###############################################################
#  Generated by:      Cadence Innovus 21.14-s109_1
#  OS:                Linux x86_64(Host ID eecs2420p06.engin.umich.edu)
#  Generated on:      Sun Mar 26 16:31:44 2023
#  Design:            PE_POOL
#  Command:           write_lef_abstract /afs/umich.edu/class/eecs627/w23/groups/group4/CNN_LSTM/CNN_POOL_ReLU/apr/PE_POOL/data/PE_POOL.lef -specifyTopLayer 4 -stripePin -PGpinLayers 4
###############################################################

VERSION 5.8 ;

BUSBITCHARS "[]" ;
DIVIDERCHAR "/" ;

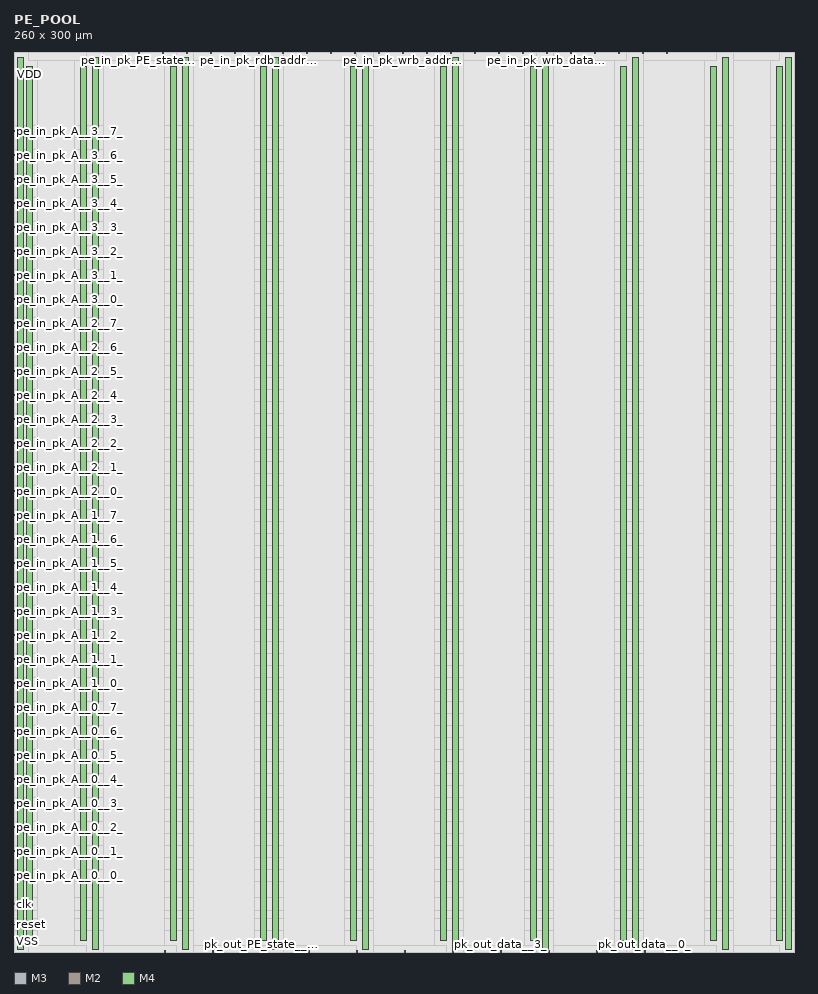
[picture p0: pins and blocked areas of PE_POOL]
MACRO PE_POOL
  CLASS BLOCK ;
  SIZE 260.000000 BY 300.000000 ;
  FOREIGN PE_POOL 0.000000 0.000000 ;
  ORIGIN 0 0 ;
  SYMMETRY X Y R90 ;
  PIN clk
    DIRECTION INPUT ;
    USE SIGNAL ;
    ANTENNAPARTIALMETALAREA 1.54 LAYER M3  ;
    ANTENNAPARTIALMETALSIDEAREA 0.0158 LAYER M3  ;
    ANTENNAMODEL OXIDE1 ;
    ANTENNAGATEAREA 0.8352 LAYER M3  ;
    ANTENNAMAXAREACAR 2.83812 LAYER M3  ;
    ANTENNAMAXSIDEAREACAR 0.0291906 LAYER M3  ;
    ANTENNAMAXCUTCAR 0.143678 LAYER V3  ;
    PORT
      LAYER M3 ;
        RECT 0.000000 15.900000 0.600000 16.100000 ;
    END
  END clk
  PIN reset
    DIRECTION INPUT ;
    USE SIGNAL ;
    ANTENNAPARTIALMETALAREA 1.3 LAYER M3  ;
    ANTENNAPARTIALMETALSIDEAREA 0.0134 LAYER M3  ;
    ANTENNAMODEL OXIDE1 ;
    ANTENNAGATEAREA 0.4848 LAYER M3  ;
    ANTENNAMAXAREACAR 18.5759 LAYER M3  ;
    ANTENNAMAXSIDEAREACAR 0.186427 LAYER M3  ;
    ANTENNAMAXCUTCAR 0.330033 LAYER V3  ;
    PORT
      LAYER M3 ;
        RECT 0.000000 9.100000 0.600000 9.300000 ;
    END
  END reset
  PIN pe_in_pk_PE_state__2_
    DIRECTION INPUT ;
    USE SIGNAL ;
    ANTENNAPARTIALMETALAREA 5.1 LAYER M2  ;
    ANTENNAPARTIALMETALSIDEAREA 0.051 LAYER M2  ;
    ANTENNAMODEL OXIDE1 ;
    ANTENNAGATEAREA 0.0624 LAYER M2  ;
    ANTENNAMAXAREACAR 84.1667 LAYER M2  ;
    ANTENNAMAXSIDEAREACAR 0.842308 LAYER M2  ;
    ANTENNAMAXCUTCAR 0.641026 LAYER V2  ;
    PORT
      LAYER M2 ;
        RECT 57.500000 299.400000 57.700000 300.000000 ;
    END
  END pe_in_pk_PE_state__2_
  PIN pe_in_pk_PE_state__1_
    DIRECTION INPUT ;
    USE SIGNAL ;
    ANTENNAPARTIALMETALAREA 3.98 LAYER M2  ;
    ANTENNAPARTIALMETALSIDEAREA 0.0398 LAYER M2  ;
    ANTENNAPARTIALCUTAREA 0.08 LAYER V2  ;
    ANTENNAPARTIALMETALAREA 0.84 LAYER M3  ;
    ANTENNAPARTIALMETALSIDEAREA 0.0088 LAYER M3  ;
    ANTENNAMODEL OXIDE1 ;
    ANTENNAGATEAREA 0.0624 LAYER M3  ;
    ANTENNAMAXAREACAR 30.641 LAYER M3  ;
    ANTENNAMAXSIDEAREACAR 0.319872 LAYER M3  ;
    ANTENNAMAXCUTCAR 1.92308 LAYER V3  ;
    PORT
      LAYER M2 ;
        RECT 49.500000 299.400000 49.700000 300.000000 ;
    END
  END pe_in_pk_PE_state__1_
  PIN pe_in_pk_PE_state__0_
    DIRECTION INPUT ;
    USE SIGNAL ;
    ANTENNAPARTIALMETALAREA 3.26 LAYER M2  ;
    ANTENNAPARTIALMETALSIDEAREA 0.0326 LAYER M2  ;
    ANTENNAPARTIALCUTAREA 0.08 LAYER V2  ;
    ANTENNAPARTIALMETALAREA 0.92 LAYER M3  ;
    ANTENNAPARTIALMETALSIDEAREA 0.0096 LAYER M3  ;
    ANTENNAMODEL OXIDE1 ;
    ANTENNAGATEAREA 0.0624 LAYER M3  ;
    ANTENNAMAXAREACAR 57.5641 LAYER M3  ;
    ANTENNAMAXSIDEAREACAR 0.589103 LAYER M3  ;
    ANTENNAMAXCUTCAR 1.92308 LAYER V3  ;
    PORT
      LAYER M2 ;
        RECT 41.500000 299.400000 41.700000 300.000000 ;
    END
  END pe_in_pk_PE_state__0_
  PIN pe_in_pk_A__3__7_
    DIRECTION INPUT ;
    USE SIGNAL ;
    ANTENNAPARTIALMETALAREA 3.58 LAYER M3  ;
    ANTENNAPARTIALMETALSIDEAREA 0.0358 LAYER M3  ;
    ANTENNAMODEL OXIDE1 ;
    ANTENNAGATEAREA 0.0624 LAYER M3  ;
    ANTENNAMAXAREACAR 68.141 LAYER M3  ;
    ANTENNAMAXSIDEAREACAR 0.688462 LAYER M3  ;
    ANTENNAMAXCUTCAR 1.92308 LAYER V3  ;
    PORT
      LAYER M3 ;
        RECT 0.000000 273.500000 0.600000 273.700000 ;
    END
  END pe_in_pk_A__3__7_
  PIN pe_in_pk_A__3__6_
    DIRECTION INPUT ;
    USE SIGNAL ;
    ANTENNAPARTIALMETALAREA 2.54 LAYER M3  ;
    ANTENNAPARTIALMETALSIDEAREA 0.0254 LAYER M3  ;
    ANTENNAMODEL OXIDE1 ;
    ANTENNAGATEAREA 0.0624 LAYER M3  ;
    ANTENNAMAXAREACAR 48.9103 LAYER M3  ;
    ANTENNAMAXSIDEAREACAR 0.496154 LAYER M3  ;
    ANTENNAMAXCUTCAR 1.92308 LAYER V3  ;
    PORT
      LAYER M3 ;
        RECT 0.000000 265.500000 0.600000 265.700000 ;
    END
  END pe_in_pk_A__3__6_
  PIN pe_in_pk_A__3__5_
    DIRECTION INPUT ;
    USE SIGNAL ;
    ANTENNAPARTIALMETALAREA 2.14 LAYER M3  ;
    ANTENNAPARTIALMETALSIDEAREA 0.0214 LAYER M3  ;
    ANTENNAMODEL OXIDE1 ;
    ANTENNAGATEAREA 0.0624 LAYER M3  ;
    ANTENNAMAXAREACAR 39.9359 LAYER M3  ;
    ANTENNAMAXSIDEAREACAR 0.40641 LAYER M3  ;
    ANTENNAMAXCUTCAR 1.92308 LAYER V3  ;
    PORT
      LAYER M3 ;
        RECT 0.000000 257.500000 0.600000 257.700000 ;
    END
  END pe_in_pk_A__3__5_
  PIN pe_in_pk_A__3__4_
    DIRECTION INPUT ;
    USE SIGNAL ;
    ANTENNAPARTIALMETALAREA 2.06 LAYER M3  ;
    ANTENNAPARTIALMETALSIDEAREA 0.0206 LAYER M3  ;
    ANTENNAMODEL OXIDE1 ;
    ANTENNAGATEAREA 0.0624 LAYER M3  ;
    ANTENNAMAXAREACAR 37.3718 LAYER M3  ;
    ANTENNAMAXSIDEAREACAR 0.380769 LAYER M3  ;
    ANTENNAMAXCUTCAR 1.92308 LAYER V3  ;
    PORT
      LAYER M3 ;
        RECT 0.000000 249.500000 0.600000 249.700000 ;
    END
  END pe_in_pk_A__3__4_
  PIN pe_in_pk_A__3__3_
    DIRECTION INPUT ;
    USE SIGNAL ;
    ANTENNAPARTIALMETALAREA 1.82 LAYER M3  ;
    ANTENNAPARTIALMETALSIDEAREA 0.0182 LAYER M3  ;
    ANTENNAMODEL OXIDE1 ;
    ANTENNAGATEAREA 0.0624 LAYER M3  ;
    ANTENNAMAXAREACAR 34.8077 LAYER M3  ;
    ANTENNAMAXSIDEAREACAR 0.355128 LAYER M3  ;
    ANTENNAMAXCUTCAR 1.92308 LAYER V3  ;
    PORT
      LAYER M3 ;
        RECT 0.000000 241.500000 0.600000 241.700000 ;
    END
  END pe_in_pk_A__3__3_
  PIN pe_in_pk_A__3__2_
    DIRECTION INPUT ;
    USE SIGNAL ;
    ANTENNAPARTIALMETALAREA 2.06 LAYER M3  ;
    ANTENNAPARTIALMETALSIDEAREA 0.0206 LAYER M3  ;
    ANTENNAMODEL OXIDE1 ;
    ANTENNAGATEAREA 0.0624 LAYER M3  ;
    ANTENNAMAXAREACAR 41.2179 LAYER M3  ;
    ANTENNAMAXSIDEAREACAR 0.419231 LAYER M3  ;
    ANTENNAMAXCUTCAR 1.92308 LAYER V3  ;
    PORT
      LAYER M3 ;
        RECT 0.000000 233.500000 0.600000 233.700000 ;
    END
  END pe_in_pk_A__3__2_
  PIN pe_in_pk_A__3__1_
    DIRECTION INPUT ;
    USE SIGNAL ;
    ANTENNAPARTIALMETALAREA 2.14 LAYER M3  ;
    ANTENNAPARTIALMETALSIDEAREA 0.0214 LAYER M3  ;
    ANTENNAMODEL OXIDE1 ;
    ANTENNAGATEAREA 0.0624 LAYER M3  ;
    ANTENNAMAXAREACAR 38.6538 LAYER M3  ;
    ANTENNAMAXSIDEAREACAR 0.39359 LAYER M3  ;
    ANTENNAMAXCUTCAR 1.92308 LAYER V3  ;
    PORT
      LAYER M3 ;
        RECT 0.000000 225.500000 0.600000 225.700000 ;
    END
  END pe_in_pk_A__3__1_
  PIN pe_in_pk_A__3__0_
    DIRECTION INPUT ;
    USE SIGNAL ;
    ANTENNAPARTIALMETALAREA 2.06 LAYER M3  ;
    ANTENNAPARTIALMETALSIDEAREA 0.0206 LAYER M3  ;
    ANTENNAMODEL OXIDE1 ;
    ANTENNAGATEAREA 0.0624 LAYER M3  ;
    ANTENNAMAXAREACAR 46.3462 LAYER M3  ;
    ANTENNAMAXSIDEAREACAR 0.470513 LAYER M3  ;
    ANTENNAMAXCUTCAR 1.92308 LAYER V3  ;
    PORT
      LAYER M3 ;
        RECT 0.000000 217.500000 0.600000 217.700000 ;
    END
  END pe_in_pk_A__3__0_
  PIN pe_in_pk_A__2__7_
    DIRECTION INPUT ;
    USE SIGNAL ;
    ANTENNAPARTIALMETALAREA 1.82 LAYER M3  ;
    ANTENNAPARTIALMETALSIDEAREA 0.0182 LAYER M3  ;
    ANTENNAMODEL OXIDE1 ;
    ANTENNAGATEAREA 0.0624 LAYER M3  ;
    ANTENNAMAXAREACAR 42.5 LAYER M3  ;
    ANTENNAMAXSIDEAREACAR 0.432051 LAYER M3  ;
    ANTENNAMAXCUTCAR 1.92308 LAYER V3  ;
    PORT
      LAYER M3 ;
        RECT 0.000000 209.500000 0.600000 209.700000 ;
    END
  END pe_in_pk_A__2__7_
  PIN pe_in_pk_A__2__6_
    DIRECTION INPUT ;
    USE SIGNAL ;
    ANTENNAPARTIALMETALAREA 1.58 LAYER M3  ;
    ANTENNAPARTIALMETALSIDEAREA 0.0158 LAYER M3  ;
    ANTENNAMODEL OXIDE1 ;
    ANTENNAGATEAREA 0.0624 LAYER M3  ;
    ANTENNAMAXAREACAR 38.6538 LAYER M3  ;
    ANTENNAMAXSIDEAREACAR 0.39359 LAYER M3  ;
    ANTENNAMAXCUTCAR 1.92308 LAYER V3  ;
    PORT
      LAYER M3 ;
        RECT 0.000000 201.500000 0.600000 201.700000 ;
    END
  END pe_in_pk_A__2__6_
  PIN pe_in_pk_A__2__5_
    DIRECTION INPUT ;
    USE SIGNAL ;
    ANTENNAPARTIALMETALAREA 1.74 LAYER M3  ;
    ANTENNAPARTIALMETALSIDEAREA 0.0174 LAYER M3  ;
    ANTENNAMODEL OXIDE1 ;
    ANTENNAGATEAREA 0.0624 LAYER M3  ;
    ANTENNAMAXAREACAR 38.6538 LAYER M3  ;
    ANTENNAMAXSIDEAREACAR 0.39359 LAYER M3  ;
    ANTENNAMAXCUTCAR 1.92308 LAYER V3  ;
    PORT
      LAYER M3 ;
        RECT 0.000000 193.500000 0.600000 193.700000 ;
    END
  END pe_in_pk_A__2__5_
  PIN pe_in_pk_A__2__4_
    DIRECTION INPUT ;
    USE SIGNAL ;
    ANTENNAPARTIALMETALAREA 1.9 LAYER M3  ;
    ANTENNAPARTIALMETALSIDEAREA 0.019 LAYER M3  ;
    ANTENNAMODEL OXIDE1 ;
    ANTENNAGATEAREA 0.0624 LAYER M3  ;
    ANTENNAMAXAREACAR 36.0897 LAYER M3  ;
    ANTENNAMAXSIDEAREACAR 0.367949 LAYER M3  ;
    ANTENNAMAXCUTCAR 1.92308 LAYER V3  ;
    PORT
      LAYER M3 ;
        RECT 0.000000 185.500000 0.600000 185.700000 ;
    END
  END pe_in_pk_A__2__4_
  PIN pe_in_pk_A__2__3_
    DIRECTION INPUT ;
    USE SIGNAL ;
    ANTENNAPARTIALMETALAREA 1.66 LAYER M3  ;
    ANTENNAPARTIALMETALSIDEAREA 0.0166 LAYER M3  ;
    ANTENNAMODEL OXIDE1 ;
    ANTENNAGATEAREA 0.0624 LAYER M3  ;
    ANTENNAMAXAREACAR 38.6538 LAYER M3  ;
    ANTENNAMAXSIDEAREACAR 0.39359 LAYER M3  ;
    ANTENNAMAXCUTCAR 1.92308 LAYER V3  ;
    PORT
      LAYER M3 ;
        RECT 0.000000 177.500000 0.600000 177.700000 ;
    END
  END pe_in_pk_A__2__3_
  PIN pe_in_pk_A__2__2_
    DIRECTION INPUT ;
    USE SIGNAL ;
    ANTENNAPARTIALMETALAREA 1.66 LAYER M3  ;
    ANTENNAPARTIALMETALSIDEAREA 0.0166 LAYER M3  ;
    ANTENNAMODEL OXIDE1 ;
    ANTENNAGATEAREA 0.0624 LAYER M3  ;
    ANTENNAMAXAREACAR 32.2436 LAYER M3  ;
    ANTENNAMAXSIDEAREACAR 0.329487 LAYER M3  ;
    ANTENNAMAXCUTCAR 1.92308 LAYER V3  ;
    PORT
      LAYER M3 ;
        RECT 0.000000 169.500000 0.600000 169.700000 ;
    END
  END pe_in_pk_A__2__2_
  PIN pe_in_pk_A__2__1_
    DIRECTION INPUT ;
    USE SIGNAL ;
    ANTENNAPARTIALMETALAREA 1.66 LAYER M3  ;
    ANTENNAPARTIALMETALSIDEAREA 0.0166 LAYER M3  ;
    ANTENNAMODEL OXIDE1 ;
    ANTENNAGATEAREA 0.0624 LAYER M3  ;
    ANTENNAMAXAREACAR 34.8077 LAYER M3  ;
    ANTENNAMAXSIDEAREACAR 0.355128 LAYER M3  ;
    ANTENNAMAXCUTCAR 1.92308 LAYER V3  ;
    PORT
      LAYER M3 ;
        RECT 0.000000 161.500000 0.600000 161.700000 ;
    END
  END pe_in_pk_A__2__1_
  PIN pe_in_pk_A__2__0_
    DIRECTION INPUT ;
    USE SIGNAL ;
    ANTENNAPARTIALMETALAREA 1.66 LAYER M3  ;
    ANTENNAPARTIALMETALSIDEAREA 0.0166 LAYER M3  ;
    ANTENNAMODEL OXIDE1 ;
    ANTENNAGATEAREA 0.0624 LAYER M3  ;
    ANTENNAMAXAREACAR 37.3718 LAYER M3  ;
    ANTENNAMAXSIDEAREACAR 0.380769 LAYER M3  ;
    ANTENNAMAXCUTCAR 1.92308 LAYER V3  ;
    PORT
      LAYER M3 ;
        RECT 0.000000 153.500000 0.600000 153.700000 ;
    END
  END pe_in_pk_A__2__0_
  PIN pe_in_pk_A__1__7_
    DIRECTION INPUT ;
    USE SIGNAL ;
    ANTENNAPARTIALMETALAREA 1.42 LAYER M3  ;
    ANTENNAPARTIALMETALSIDEAREA 0.0142 LAYER M3  ;
    ANTENNAMODEL OXIDE1 ;
    ANTENNAGATEAREA 0.0624 LAYER M3  ;
    ANTENNAMAXAREACAR 39.9359 LAYER M3  ;
    ANTENNAMAXSIDEAREACAR 0.40641 LAYER M3  ;
    ANTENNAMAXCUTCAR 1.92308 LAYER V3  ;
    PORT
      LAYER M3 ;
        RECT 0.000000 145.500000 0.600000 145.700000 ;
    END
  END pe_in_pk_A__1__7_
  PIN pe_in_pk_A__1__6_
    DIRECTION INPUT ;
    USE SIGNAL ;
    ANTENNAPARTIALMETALAREA 1.5 LAYER M3  ;
    ANTENNAPARTIALMETALSIDEAREA 0.015 LAYER M3  ;
    ANTENNAPARTIALCUTAREA 0.08 LAYER V3  ;
    ANTENNAPARTIALMETALAREA 0.28 LAYER M4  ;
    ANTENNAPARTIALMETALSIDEAREA 0.0032 LAYER M4  ;
    ANTENNAMODEL OXIDE1 ;
    ANTENNAGATEAREA 0.0624 LAYER M4  ;
    ANTENNAMAXAREACAR 36.4103 LAYER M4  ;
    ANTENNAMAXSIDEAREACAR 0.383974 LAYER M4  ;
    ANTENNAMAXCUTCAR 3.20513 LAYER V4  ;
    PORT
      LAYER M3 ;
        RECT 0.000000 137.500000 0.600000 137.700000 ;
    END
  END pe_in_pk_A__1__6_
  PIN pe_in_pk_A__1__5_
    DIRECTION INPUT ;
    USE SIGNAL ;
    ANTENNAPARTIALMETALAREA 1.74 LAYER M3  ;
    ANTENNAPARTIALMETALSIDEAREA 0.0174 LAYER M3  ;
    ANTENNAMODEL OXIDE1 ;
    ANTENNAGATEAREA 0.0624 LAYER M3  ;
    ANTENNAMAXAREACAR 47.6282 LAYER M3  ;
    ANTENNAMAXSIDEAREACAR 0.483333 LAYER M3  ;
    ANTENNAMAXCUTCAR 1.92308 LAYER V3  ;
    PORT
      LAYER M3 ;
        RECT 0.000000 129.500000 0.600000 129.700000 ;
    END
  END pe_in_pk_A__1__5_
  PIN pe_in_pk_A__1__4_
    DIRECTION INPUT ;
    USE SIGNAL ;
    ANTENNAPARTIALMETALAREA 1.74 LAYER M3  ;
    ANTENNAPARTIALMETALSIDEAREA 0.0174 LAYER M3  ;
    ANTENNAMODEL OXIDE1 ;
    ANTENNAGATEAREA 0.0624 LAYER M3  ;
    ANTENNAMAXAREACAR 45.0641 LAYER M3  ;
    ANTENNAMAXSIDEAREACAR 0.457692 LAYER M3  ;
    ANTENNAMAXCUTCAR 1.92308 LAYER V3  ;
    PORT
      LAYER M3 ;
        RECT 0.000000 121.500000 0.600000 121.700000 ;
    END
  END pe_in_pk_A__1__4_
  PIN pe_in_pk_A__1__3_
    DIRECTION INPUT ;
    USE SIGNAL ;
    ANTENNAPARTIALMETALAREA 1.74 LAYER M3  ;
    ANTENNAPARTIALMETALSIDEAREA 0.0174 LAYER M3  ;
    ANTENNAMODEL OXIDE1 ;
    ANTENNAGATEAREA 0.0624 LAYER M3  ;
    ANTENNAMAXAREACAR 33.5256 LAYER M3  ;
    ANTENNAMAXSIDEAREACAR 0.342308 LAYER M3  ;
    ANTENNAMAXCUTCAR 1.92308 LAYER V3  ;
    PORT
      LAYER M3 ;
        RECT 0.000000 113.500000 0.600000 113.700000 ;
    END
  END pe_in_pk_A__1__3_
  PIN pe_in_pk_A__1__2_
    DIRECTION INPUT ;
    USE SIGNAL ;
    ANTENNAPARTIALMETALAREA 1.82 LAYER M3  ;
    ANTENNAPARTIALMETALSIDEAREA 0.0182 LAYER M3  ;
    ANTENNAMODEL OXIDE1 ;
    ANTENNAGATEAREA 0.0624 LAYER M3  ;
    ANTENNAMAXAREACAR 56.6026 LAYER M3  ;
    ANTENNAMAXSIDEAREACAR 0.573077 LAYER M3  ;
    ANTENNAMAXCUTCAR 1.92308 LAYER V3  ;
    PORT
      LAYER M3 ;
        RECT 0.000000 105.500000 0.600000 105.700000 ;
    END
  END pe_in_pk_A__1__2_
  PIN pe_in_pk_A__1__1_
    DIRECTION INPUT ;
    USE SIGNAL ;
    ANTENNAPARTIALMETALAREA 1.74 LAYER M3  ;
    ANTENNAPARTIALMETALSIDEAREA 0.0174 LAYER M3  ;
    ANTENNAMODEL OXIDE1 ;
    ANTENNAGATEAREA 0.0624 LAYER M3  ;
    ANTENNAMAXAREACAR 52.7564 LAYER M3  ;
    ANTENNAMAXSIDEAREACAR 0.534615 LAYER M3  ;
    ANTENNAMAXCUTCAR 1.28205 LAYER V3  ;
    PORT
      LAYER M3 ;
        RECT 0.000000 97.500000 0.600000 97.700000 ;
    END
  END pe_in_pk_A__1__1_
  PIN pe_in_pk_A__1__0_
    DIRECTION INPUT ;
    USE SIGNAL ;
    ANTENNAPARTIALMETALAREA 1.5 LAYER M3  ;
    ANTENNAPARTIALMETALSIDEAREA 0.015 LAYER M3  ;
    ANTENNAMODEL OXIDE1 ;
    ANTENNAGATEAREA 0.0624 LAYER M3  ;
    ANTENNAMAXAREACAR 32.2436 LAYER M3  ;
    ANTENNAMAXSIDEAREACAR 0.329487 LAYER M3  ;
    ANTENNAMAXCUTCAR 1.92308 LAYER V3  ;
    PORT
      LAYER M3 ;
        RECT 0.000000 89.500000 0.600000 89.700000 ;
    END
  END pe_in_pk_A__1__0_
  PIN pe_in_pk_A__0__7_
    DIRECTION INPUT ;
    USE SIGNAL ;
    ANTENNAPARTIALMETALAREA 1.82 LAYER M3  ;
    ANTENNAPARTIALMETALSIDEAREA 0.0182 LAYER M3  ;
    ANTENNAMODEL OXIDE1 ;
    ANTENNAGATEAREA 0.0624 LAYER M3  ;
    ANTENNAMAXAREACAR 50.1923 LAYER M3  ;
    ANTENNAMAXSIDEAREACAR 0.508974 LAYER M3  ;
    ANTENNAMAXCUTCAR 1.28205 LAYER V3  ;
    PORT
      LAYER M3 ;
        RECT 0.000000 81.500000 0.600000 81.700000 ;
    END
  END pe_in_pk_A__0__7_
  PIN pe_in_pk_A__0__6_
    DIRECTION INPUT ;
    USE SIGNAL ;
    ANTENNAPARTIALMETALAREA 1.78 LAYER M3  ;
    ANTENNAPARTIALMETALSIDEAREA 0.0182 LAYER M3  ;
    ANTENNAMODEL OXIDE1 ;
    ANTENNAGATEAREA 0.0624 LAYER M3  ;
    ANTENNAMAXAREACAR 32.8846 LAYER M3  ;
    ANTENNAMAXSIDEAREACAR 0.342308 LAYER M3  ;
    ANTENNAMAXCUTCAR 1.92308 LAYER V3  ;
    PORT
      LAYER M3 ;
        RECT 0.000000 73.500000 0.600000 73.700000 ;
    END
  END pe_in_pk_A__0__6_
  PIN pe_in_pk_A__0__5_
    DIRECTION INPUT ;
    USE SIGNAL ;
    ANTENNAPARTIALMETALAREA 1.66 LAYER M3  ;
    ANTENNAPARTIALMETALSIDEAREA 0.0166 LAYER M3  ;
    ANTENNAPARTIALCUTAREA 0.08 LAYER V3  ;
    ANTENNAPARTIALMETALAREA 0.68 LAYER M4  ;
    ANTENNAPARTIALMETALSIDEAREA 0.0072 LAYER M4  ;
    ANTENNAMODEL OXIDE1 ;
    ANTENNAGATEAREA 0.0624 LAYER M4  ;
    ANTENNAMAXAREACAR 17.1795 LAYER M4  ;
    ANTENNAMAXSIDEAREACAR 0.191667 LAYER M4  ;
    ANTENNAMAXCUTCAR 3.20513 LAYER V4  ;
    PORT
      LAYER M3 ;
        RECT 0.000000 65.500000 0.600000 65.700000 ;
    END
  END pe_in_pk_A__0__5_
  PIN pe_in_pk_A__0__4_
    DIRECTION INPUT ;
    USE SIGNAL ;
    ANTENNAPARTIALMETALAREA 1.5 LAYER M3  ;
    ANTENNAPARTIALMETALSIDEAREA 0.015 LAYER M3  ;
    ANTENNAMODEL OXIDE1 ;
    ANTENNAGATEAREA 0.0624 LAYER M3  ;
    ANTENNAMAXAREACAR 36.0897 LAYER M3  ;
    ANTENNAMAXSIDEAREACAR 0.367949 LAYER M3  ;
    ANTENNAMAXCUTCAR 1.92308 LAYER V3  ;
    PORT
      LAYER M3 ;
        RECT 0.000000 57.500000 0.600000 57.700000 ;
    END
  END pe_in_pk_A__0__4_
  PIN pe_in_pk_A__0__3_
    DIRECTION INPUT ;
    USE SIGNAL ;
    ANTENNAPARTIALMETALAREA 2.14 LAYER M3  ;
    ANTENNAPARTIALMETALSIDEAREA 0.0214 LAYER M3  ;
    ANTENNAMODEL OXIDE1 ;
    ANTENNAGATEAREA 0.0624 LAYER M3  ;
    ANTENNAMAXAREACAR 42.5 LAYER M3  ;
    ANTENNAMAXSIDEAREACAR 0.432051 LAYER M3  ;
    ANTENNAMAXCUTCAR 1.92308 LAYER V3  ;
    PORT
      LAYER M3 ;
        RECT 0.000000 49.500000 0.600000 49.700000 ;
    END
  END pe_in_pk_A__0__3_
  PIN pe_in_pk_A__0__2_
    DIRECTION INPUT ;
    USE SIGNAL ;
    ANTENNAPARTIALMETALAREA 1.66 LAYER M3  ;
    ANTENNAPARTIALMETALSIDEAREA 0.0166 LAYER M3  ;
    ANTENNAMODEL OXIDE1 ;
    ANTENNAGATEAREA 0.0624 LAYER M3  ;
    ANTENNAMAXAREACAR 32.2436 LAYER M3  ;
    ANTENNAMAXSIDEAREACAR 0.329487 LAYER M3  ;
    ANTENNAMAXCUTCAR 1.92308 LAYER V3  ;
    PORT
      LAYER M3 ;
        RECT 0.000000 41.500000 0.600000 41.700000 ;
    END
  END pe_in_pk_A__0__2_
  PIN pe_in_pk_A__0__1_
    DIRECTION INPUT ;
    USE SIGNAL ;
    ANTENNAPARTIALMETALAREA 1.58 LAYER M3  ;
    ANTENNAPARTIALMETALSIDEAREA 0.0158 LAYER M3  ;
    ANTENNAMODEL OXIDE1 ;
    ANTENNAGATEAREA 0.0624 LAYER M3  ;
    ANTENNAMAXAREACAR 29.6795 LAYER M3  ;
    ANTENNAMAXSIDEAREACAR 0.303846 LAYER M3  ;
    ANTENNAMAXCUTCAR 1.92308 LAYER V3  ;
    PORT
      LAYER M3 ;
        RECT 0.000000 33.500000 0.600000 33.700000 ;
    END
  END pe_in_pk_A__0__1_
  PIN pe_in_pk_A__0__0_
    DIRECTION INPUT ;
    USE SIGNAL ;
    ANTENNAPARTIALMETALAREA 1.66 LAYER M3  ;
    ANTENNAPARTIALMETALSIDEAREA 0.0166 LAYER M3  ;
    ANTENNAMODEL OXIDE1 ;
    ANTENNAGATEAREA 0.0624 LAYER M3  ;
    ANTENNAMAXAREACAR 46.3462 LAYER M3  ;
    ANTENNAMAXSIDEAREACAR 0.470513 LAYER M3  ;
    ANTENNAMAXCUTCAR 1.92308 LAYER V3  ;
    PORT
      LAYER M3 ;
        RECT 0.000000 25.500000 0.600000 25.700000 ;
    END
  END pe_in_pk_A__0__0_
  PIN pe_in_pk_wrb_data__7_
    DIRECTION INPUT ;
    USE SIGNAL ;
    ANTENNAPARTIALMETALAREA 5.74 LAYER M2  ;
    ANTENNAPARTIALMETALSIDEAREA 0.0574 LAYER M2  ;
    ANTENNAPARTIALCUTAREA 0.08 LAYER V2  ;
    ANTENNAPARTIALMETALAREA 5 LAYER M3  ;
    ANTENNAPARTIALMETALSIDEAREA 0.0504 LAYER M3  ;
    ANTENNAMODEL OXIDE1 ;
    ANTENNAGATEAREA 0.1272 LAYER M3  ;
    ANTENNAMAXAREACAR 43.1447 LAYER M3  ;
    ANTENNAMAXSIDEAREACAR 0.437736 LAYER M3  ;
    ANTENNAMAXCUTCAR 1.25786 LAYER V3  ;
    PORT
      LAYER M2 ;
        RECT 217.500000 299.400000 217.700000 300.000000 ;
    END
  END pe_in_pk_wrb_data__7_
  PIN pe_in_pk_wrb_data__6_
    DIRECTION INPUT ;
    USE SIGNAL ;
    ANTENNAPARTIALMETALAREA 3.34 LAYER M2  ;
    ANTENNAPARTIALMETALSIDEAREA 0.0334 LAYER M2  ;
    ANTENNAPARTIALCUTAREA 0.08 LAYER V2  ;
    ANTENNAPARTIALMETALAREA 3.64 LAYER M3  ;
    ANTENNAPARTIALMETALSIDEAREA 0.0368 LAYER M3  ;
    ANTENNAMODEL OXIDE1 ;
    ANTENNAGATEAREA 0.0624 LAYER M3  ;
    ANTENNAMAXAREACAR 62.6923 LAYER M3  ;
    ANTENNAMAXSIDEAREACAR 0.640385 LAYER M3  ;
    ANTENNAMAXCUTCAR 1.92308 LAYER V3  ;
    PORT
      LAYER M2 ;
        RECT 209.500000 299.400000 209.700000 300.000000 ;
    END
  END pe_in_pk_wrb_data__6_
  PIN pe_in_pk_wrb_data__5_
    DIRECTION INPUT ;
    USE SIGNAL ;
    ANTENNAPARTIALMETALAREA 7.42 LAYER M2  ;
    ANTENNAPARTIALMETALSIDEAREA 0.0742 LAYER M2  ;
    ANTENNAPARTIALCUTAREA 0.08 LAYER V2  ;
    ANTENNAPARTIALMETALAREA 1.8 LAYER M3  ;
    ANTENNAPARTIALMETALSIDEAREA 0.0184 LAYER M3  ;
    ANTENNAMODEL OXIDE1 ;
    ANTENNAGATEAREA 0.1272 LAYER M3  ;
    ANTENNAMAXAREACAR 18.6164 LAYER M3  ;
    ANTENNAMAXSIDEAREACAR 0.192453 LAYER M3  ;
    ANTENNAMAXCUTCAR 1.25786 LAYER V3  ;
    PORT
      LAYER M2 ;
        RECT 201.500000 299.400000 201.700000 300.000000 ;
    END
  END pe_in_pk_wrb_data__5_
  PIN pe_in_pk_wrb_data__4_
    DIRECTION INPUT ;
    USE SIGNAL ;
    ANTENNAPARTIALMETALAREA 6.48 LAYER M2  ;
    ANTENNAPARTIALMETALSIDEAREA 0.0648 LAYER M2  ;
    ANTENNAMODEL OXIDE1 ;
    ANTENNAGATEAREA 0.0624 LAYER M2  ;
    ANTENNAMAXAREACAR 106.282 LAYER M2  ;
    ANTENNAMAXSIDEAREACAR 1.06346 LAYER M2  ;
    ANTENNAMAXCUTCAR 0.641026 LAYER V2  ;
    PORT
      LAYER M2 ;
        RECT 193.500000 299.400000 193.700000 300.000000 ;
    END
  END pe_in_pk_wrb_data__4_
  PIN pe_in_pk_wrb_data__3_
    DIRECTION INPUT ;
    USE SIGNAL ;
    ANTENNAPARTIALMETALAREA 3.42 LAYER M2  ;
    ANTENNAPARTIALMETALSIDEAREA 0.0342 LAYER M2  ;
    ANTENNAMODEL OXIDE1 ;
    ANTENNAGATEAREA 0.0624 LAYER M2  ;
    ANTENNAMAXAREACAR 57.2436 LAYER M2  ;
    ANTENNAMAXSIDEAREACAR 0.573077 LAYER M2  ;
    ANTENNAMAXCUTCAR 0.641026 LAYER V2  ;
    PORT
      LAYER M2 ;
        RECT 185.500000 299.400000 185.700000 300.000000 ;
    END
  END pe_in_pk_wrb_data__3_
  PIN pe_in_pk_wrb_data__2_
    DIRECTION INPUT ;
    USE SIGNAL ;
    ANTENNAPARTIALMETALAREA 1.5 LAYER M2  ;
    ANTENNAPARTIALMETALSIDEAREA 0.015 LAYER M2  ;
    ANTENNAPARTIALCUTAREA 0.08 LAYER V2  ;
    ANTENNAPARTIALMETALAREA 0.6 LAYER M3  ;
    ANTENNAPARTIALMETALSIDEAREA 0.0064 LAYER M3  ;
    ANTENNAPARTIALCUTAREA 0.08 LAYER V3  ;
    ANTENNAPARTIALMETALAREA 7.72 LAYER M4  ;
    ANTENNAPARTIALMETALSIDEAREA 0.0776 LAYER M4  ;
    ANTENNAMODEL OXIDE1 ;
    ANTENNAGATEAREA 0.0624 LAYER M4  ;
    ANTENNAMAXAREACAR 130 LAYER M4  ;
    ANTENNAMAXSIDEAREACAR 1.31987 LAYER M4  ;
    ANTENNAMAXCUTCAR 3.20513 LAYER V4  ;
    PORT
      LAYER M2 ;
        RECT 177.500000 299.400000 177.700000 300.000000 ;
    END
  END pe_in_pk_wrb_data__2_
  PIN pe_in_pk_wrb_data__1_
    DIRECTION INPUT ;
    USE SIGNAL ;
    ANTENNAPARTIALMETALAREA 2.78 LAYER M2  ;
    ANTENNAPARTIALMETALSIDEAREA 0.0278 LAYER M2  ;
    ANTENNAPARTIALCUTAREA 0.08 LAYER V2  ;
    ANTENNAPARTIALMETALAREA 0.2 LAYER M3  ;
    ANTENNAPARTIALMETALSIDEAREA 0.0024 LAYER M3  ;
    ANTENNAPARTIALCUTAREA 0.08 LAYER V3  ;
    ANTENNAPARTIALMETALAREA 7.88 LAYER M4  ;
    ANTENNAPARTIALMETALSIDEAREA 0.0792 LAYER M4  ;
    ANTENNAMODEL OXIDE1 ;
    ANTENNAGATEAREA 0.0624 LAYER M4  ;
    ANTENNAMAXAREACAR 132.564 LAYER M4  ;
    ANTENNAMAXSIDEAREACAR 1.34551 LAYER M4  ;
    ANTENNAMAXCUTCAR 3.20513 LAYER V4  ;
    PORT
      LAYER M2 ;
        RECT 169.500000 299.400000 169.700000 300.000000 ;
    END
  END pe_in_pk_wrb_data__1_
  PIN pe_in_pk_wrb_data__0_
    DIRECTION INPUT ;
    USE SIGNAL ;
    ANTENNAPARTIALMETALAREA 3.5 LAYER M2  ;
    ANTENNAPARTIALMETALSIDEAREA 0.035 LAYER M2  ;
    ANTENNAPARTIALCUTAREA 0.08 LAYER V2  ;
    ANTENNAPARTIALMETALAREA 1.32 LAYER M3  ;
    ANTENNAPARTIALMETALSIDEAREA 0.0136 LAYER M3  ;
    ANTENNAPARTIALCUTAREA 0.08 LAYER V3  ;
    ANTENNAPARTIALMETALAREA 8.76 LAYER M4  ;
    ANTENNAPARTIALMETALSIDEAREA 0.088 LAYER M4  ;
    ANTENNAMODEL OXIDE1 ;
    ANTENNAGATEAREA 0.1272 LAYER M4  ;
    ANTENNAMAXAREACAR 79.3082 LAYER M4  ;
    ANTENNAMAXSIDEAREACAR 0.802516 LAYER M4  ;
    ANTENNAMAXCUTCAR 1.88679 LAYER V4  ;
    PORT
      LAYER M2 ;
        RECT 161.500000 299.400000 161.700000 300.000000 ;
    END
  END pe_in_pk_wrb_data__0_
  PIN pe_in_pk_wrb_addr__3_
    DIRECTION INPUT ;
    USE SIGNAL ;
    ANTENNAPARTIALMETALAREA 0.16 LAYER M2  ;
    ANTENNAPARTIALMETALSIDEAREA 0.0016 LAYER M2  ;
    ANTENNAPARTIALCUTAREA 0.08 LAYER V2  ;
    ANTENNAPARTIALMETALAREA 4.12 LAYER M3  ;
    ANTENNAPARTIALMETALSIDEAREA 0.0416 LAYER M3  ;
    ANTENNAPARTIALCUTAREA 0.08 LAYER V3  ;
    ANTENNAPARTIALMETALAREA 14.92 LAYER M4  ;
    ANTENNAPARTIALMETALSIDEAREA 0.1496 LAYER M4  ;
    ANTENNAMODEL OXIDE1 ;
    ANTENNAGATEAREA 0.5592 LAYER M4  ;
    ANTENNAMAXAREACAR 30.7524 LAYER M4  ;
    ANTENNAMAXSIDEAREACAR 0.309317 LAYER M4  ;
    ANTENNAMAXCUTCAR 0.589153 LAYER V4  ;
    PORT
      LAYER M2 ;
        RECT 153.500000 299.400000 153.700000 300.000000 ;
    END
  END pe_in_pk_wrb_addr__3_
  PIN pe_in_pk_wrb_addr__2_
    DIRECTION INPUT ;
    USE SIGNAL ;
    ANTENNAPARTIALMETALAREA 2.46 LAYER M2  ;
    ANTENNAPARTIALMETALSIDEAREA 0.0246 LAYER M2  ;
    ANTENNAPARTIALCUTAREA 0.08 LAYER V2  ;
    ANTENNAPARTIALMETALAREA 0.84 LAYER M3  ;
    ANTENNAPARTIALMETALSIDEAREA 0.0088 LAYER M3  ;
    ANTENNAPARTIALCUTAREA 0.08 LAYER V3  ;
    ANTENNAPARTIALMETALAREA 12.52 LAYER M4  ;
    ANTENNAPARTIALMETALSIDEAREA 0.1256 LAYER M4  ;
    ANTENNAMODEL OXIDE1 ;
    ANTENNAGATEAREA 0.7536 LAYER M4  ;
    ANTENNAMAXAREACAR 22.6146 LAYER M4  ;
    ANTENNAMAXSIDEAREACAR 0.22642 LAYER M4  ;
    ANTENNAMAXCUTCAR 1.33165 LAYER V4  ;
    PORT
      LAYER M2 ;
        RECT 145.500000 299.400000 145.700000 300.000000 ;
    END
  END pe_in_pk_wrb_addr__2_
  PIN pe_in_pk_wrb_addr__1_
    DIRECTION INPUT ;
    USE SIGNAL ;
    ANTENNAPARTIALMETALAREA 2.54 LAYER M2  ;
    ANTENNAPARTIALMETALSIDEAREA 0.0254 LAYER M2  ;
    ANTENNAPARTIALCUTAREA 0.08 LAYER V2  ;
    ANTENNAPARTIALMETALAREA 0.6 LAYER M3  ;
    ANTENNAPARTIALMETALSIDEAREA 0.0064 LAYER M3  ;
    ANTENNAPARTIALCUTAREA 0.08 LAYER V3  ;
    ANTENNAPARTIALMETALAREA 11.88 LAYER M4  ;
    ANTENNAPARTIALMETALSIDEAREA 0.1192 LAYER M4  ;
    ANTENNAMODEL OXIDE1 ;
    ANTENNAGATEAREA 0.9936 LAYER M4  ;
    ANTENNAMAXAREACAR 20.7069 LAYER M4  ;
    ANTENNAMAXSIDEAREACAR 0.210811 LAYER M4  ;
    ANTENNAMAXCUTCAR 1.06091 LAYER V4  ;
    PORT
      LAYER M2 ;
        RECT 137.500000 299.400000 137.700000 300.000000 ;
    END
  END pe_in_pk_wrb_addr__1_
  PIN pe_in_pk_wrb_addr__0_
    DIRECTION INPUT ;
    USE SIGNAL ;
    ANTENNAPARTIALMETALAREA 2.46 LAYER M2  ;
    ANTENNAPARTIALMETALSIDEAREA 0.0246 LAYER M2  ;
    ANTENNAPARTIALCUTAREA 0.08 LAYER V2  ;
    ANTENNAPARTIALMETALAREA 1.4 LAYER M3  ;
    ANTENNAPARTIALMETALSIDEAREA 0.0144 LAYER M3  ;
    ANTENNAPARTIALCUTAREA 0.08 LAYER V3  ;
    ANTENNAPARTIALMETALAREA 12.84 LAYER M4  ;
    ANTENNAPARTIALMETALSIDEAREA 0.1288 LAYER M4  ;
    ANTENNAMODEL OXIDE1 ;
    ANTENNAGATEAREA 0.7536 LAYER M4  ;
    ANTENNAMAXAREACAR 26.4289 LAYER M4  ;
    ANTENNAMAXSIDEAREACAR 0.265337 LAYER M4  ;
    ANTENNAMAXCUTCAR 1.33165 LAYER V4  ;
    PORT
      LAYER M2 ;
        RECT 129.500000 299.400000 129.700000 300.000000 ;
    END
  END pe_in_pk_wrb_addr__0_
  PIN pe_in_pk_wrb__3_
    DIRECTION INPUT ;
    USE SIGNAL ;
    ANTENNAPARTIALMETALAREA 2.46 LAYER M2  ;
    ANTENNAPARTIALMETALSIDEAREA 0.0246 LAYER M2  ;
    ANTENNAPARTIALCUTAREA 0.08 LAYER V2  ;
    ANTENNAPARTIALMETALAREA 0.12 LAYER M3  ;
    ANTENNAPARTIALMETALSIDEAREA 0.0016 LAYER M3  ;
    ANTENNAPARTIALCUTAREA 0.08 LAYER V3  ;
    ANTENNAPARTIALMETALAREA 13 LAYER M4  ;
    ANTENNAPARTIALMETALSIDEAREA 0.1304 LAYER M4  ;
    ANTENNAMODEL OXIDE1 ;
    ANTENNAGATEAREA 0.1488 LAYER M4  ;
    ANTENNAMAXAREACAR 94.7399 LAYER M4  ;
    ANTENNAMAXSIDEAREACAR 0.954435 LAYER M4  ;
    ANTENNAMAXCUTCAR 1.6129 LAYER V4  ;
    PORT
      LAYER M2 ;
        RECT 121.500000 299.400000 121.700000 300.000000 ;
    END
  END pe_in_pk_wrb__3_
  PIN pe_in_pk_wrb__2_
    DIRECTION INPUT ;
    USE SIGNAL ;
    ANTENNAPARTIALMETALAREA 2.22 LAYER M2  ;
    ANTENNAPARTIALMETALSIDEAREA 0.0222 LAYER M2  ;
    ANTENNAPARTIALCUTAREA 0.08 LAYER V2  ;
    ANTENNAPARTIALMETALAREA 0.44 LAYER M3  ;
    ANTENNAPARTIALMETALSIDEAREA 0.0048 LAYER M3  ;
    ANTENNAPARTIALCUTAREA 0.08 LAYER V3  ;
    ANTENNAPARTIALMETALAREA 12.2 LAYER M4  ;
    ANTENNAPARTIALMETALSIDEAREA 0.1224 LAYER M4  ;
    ANTENNAMODEL OXIDE1 ;
    ANTENNAGATEAREA 0.2952 LAYER M4  ;
    ANTENNAMAXAREACAR 45.2412 LAYER M4  ;
    ANTENNAMAXSIDEAREACAR 0.457182 LAYER M4  ;
    ANTENNAMAXCUTCAR 0.677507 LAYER V4  ;
    PORT
      LAYER M2 ;
        RECT 113.500000 299.400000 113.700000 300.000000 ;
    END
  END pe_in_pk_wrb__2_
  PIN pe_in_pk_wrb__1_
    DIRECTION INPUT ;
    USE SIGNAL ;
    ANTENNAPARTIALMETALAREA 4.46 LAYER M2  ;
    ANTENNAPARTIALMETALSIDEAREA 0.0446 LAYER M2  ;
    ANTENNAPARTIALCUTAREA 0.08 LAYER V2  ;
    ANTENNAPARTIALMETALAREA 1.08 LAYER M3  ;
    ANTENNAPARTIALMETALSIDEAREA 0.0112 LAYER M3  ;
    ANTENNAPARTIALCUTAREA 0.08 LAYER V3  ;
    ANTENNAPARTIALMETALAREA 11.08 LAYER M4  ;
    ANTENNAPARTIALMETALSIDEAREA 0.1112 LAYER M4  ;
    ANTENNAMODEL OXIDE1 ;
    ANTENNAGATEAREA 0.2952 LAYER M4  ;
    ANTENNAMAXAREACAR 44.9702 LAYER M4  ;
    ANTENNAMAXSIDEAREACAR 0.454472 LAYER M4  ;
    ANTENNAMAXCUTCAR 0.677507 LAYER V4  ;
    PORT
      LAYER M2 ;
        RECT 105.500000 299.400000 105.700000 300.000000 ;
    END
  END pe_in_pk_wrb__1_
  PIN pe_in_pk_wrb__0_
    DIRECTION INPUT ;
    USE SIGNAL ;
    ANTENNAPARTIALMETALAREA 12.94 LAYER M2  ;
    ANTENNAPARTIALMETALSIDEAREA 0.1294 LAYER M2  ;
    ANTENNAPARTIALCUTAREA 0.08 LAYER V2  ;
    ANTENNAPARTIALMETALAREA 4.84 LAYER M3  ;
    ANTENNAPARTIALMETALSIDEAREA 0.0488 LAYER M3  ;
    ANTENNAPARTIALCUTAREA 0.08 LAYER V3  ;
    ANTENNAPARTIALMETALAREA 1.8 LAYER M4  ;
    ANTENNAPARTIALMETALSIDEAREA 0.0184 LAYER M4  ;
    ANTENNAMODEL OXIDE1 ;
    ANTENNAGATEAREA 0.2952 LAYER M4  ;
    ANTENNAMAXAREACAR 11.0949 LAYER M4  ;
    ANTENNAMAXSIDEAREACAR 0.115718 LAYER M4  ;
    ANTENNAMAXCUTCAR 0.677507 LAYER V4  ;
    PORT
      LAYER M2 ;
        RECT 97.500000 299.400000 97.700000 300.000000 ;
    END
  END pe_in_pk_wrb__0_
  PIN pe_in_pk_rdb_addr__3_
    DIRECTION INPUT ;
    USE SIGNAL ;
    ANTENNAPARTIALMETALAREA 5.1 LAYER M2  ;
    ANTENNAPARTIALMETALSIDEAREA 0.051 LAYER M2  ;
    ANTENNAPARTIALCUTAREA 0.08 LAYER V2  ;
    ANTENNAPARTIALMETALAREA 3.64 LAYER M3  ;
    ANTENNAPARTIALMETALSIDEAREA 0.0368 LAYER M3  ;
    ANTENNAPARTIALCUTAREA 0.08 LAYER V3  ;
    ANTENNAPARTIALMETALAREA 9.88 LAYER M4  ;
    ANTENNAPARTIALMETALSIDEAREA 0.0992 LAYER M4  ;
    ANTENNAMODEL OXIDE1 ;
    ANTENNAGATEAREA 0.3192 LAYER M4  ;
    ANTENNAMAXAREACAR 36.5205 LAYER M4  ;
    ANTENNAMAXSIDEAREACAR 0.368147 LAYER M4  ;
    ANTENNAMAXCUTCAR 1.01986 LAYER V4  ;
    PORT
      LAYER M2 ;
        RECT 89.500000 299.400000 89.700000 300.000000 ;
    END
  END pe_in_pk_rdb_addr__3_
  PIN pe_in_pk_rdb_addr__2_
    DIRECTION INPUT ;
    USE SIGNAL ;
    ANTENNAPARTIALMETALAREA 0.16 LAYER M2  ;
    ANTENNAPARTIALMETALSIDEAREA 0.0016 LAYER M2  ;
    ANTENNAPARTIALCUTAREA 0.08 LAYER V2  ;
    ANTENNAPARTIALMETALAREA 10.16 LAYER M3  ;
    ANTENNAPARTIALMETALSIDEAREA 0.1024 LAYER M3  ;
    ANTENNAMODEL OXIDE1 ;
    ANTENNAGATEAREA 0.5304 LAYER M3  ;
    ANTENNAMAXAREACAR 31.0349 LAYER M3  ;
    ANTENNAMAXSIDEAREACAR 0.316064 LAYER M3  ;
    ANTENNAMAXCUTCAR 0.903965 LAYER V3  ;
    PORT
      LAYER M2 ;
        RECT 81.500000 299.400000 81.700000 300.000000 ;
    END
  END pe_in_pk_rdb_addr__2_
  PIN pe_in_pk_rdb_addr__1_
    DIRECTION INPUT ;
    USE SIGNAL ;
    ANTENNAPARTIALMETALAREA 3.1 LAYER M2  ;
    ANTENNAPARTIALMETALSIDEAREA 0.031 LAYER M2  ;
    ANTENNAPARTIALCUTAREA 0.08 LAYER V2  ;
    ANTENNAPARTIALMETALAREA 11.64 LAYER M3  ;
    ANTENNAPARTIALMETALSIDEAREA 0.1168 LAYER M3  ;
    ANTENNAMODEL OXIDE1 ;
    ANTENNAGATEAREA 0.5304 LAYER M3  ;
    ANTENNAMAXAREACAR 26.6439 LAYER M3  ;
    ANTENNAMAXSIDEAREACAR 0.274941 LAYER M3  ;
    ANTENNAMAXCUTCAR 1.35135 LAYER V3  ;
    PORT
      LAYER M2 ;
        RECT 73.500000 299.400000 73.700000 300.000000 ;
    END
  END pe_in_pk_rdb_addr__1_
  PIN pe_in_pk_rdb_addr__0_
    DIRECTION INPUT ;
    USE SIGNAL ;
    ANTENNAPARTIALMETALAREA 2.62 LAYER M2  ;
    ANTENNAPARTIALMETALSIDEAREA 0.0262 LAYER M2  ;
    ANTENNAPARTIALCUTAREA 0.08 LAYER V2  ;
    ANTENNAPARTIALMETALAREA 14.2 LAYER M3  ;
    ANTENNAPARTIALMETALSIDEAREA 0.1424 LAYER M3  ;
    ANTENNAMODEL OXIDE1 ;
    ANTENNAGATEAREA 0.7368 LAYER M3  ;
    ANTENNAMAXAREACAR 22.4426 LAYER M3  ;
    ANTENNAMAXSIDEAREACAR 0.230003 LAYER M3  ;
    ANTENNAMAXCUTCAR 1.02041 LAYER V3  ;
    PORT
      LAYER M2 ;
        RECT 65.500000 299.400000 65.700000 300.000000 ;
    END
  END pe_in_pk_rdb_addr__0_
  PIN pk_out_PE_state__2_
    DIRECTION OUTPUT ;
    USE SIGNAL ;
    ANTENNAPARTIALMETALAREA 5.74 LAYER M2  ;
    ANTENNAPARTIALMETALSIDEAREA 0.0574 LAYER M2  ;
    ANTENNAPARTIALCUTAREA 0.08 LAYER V2  ;
    ANTENNADIFFAREA 2.014 LAYER M3  ;
    ANTENNAPARTIALMETALAREA 0.52 LAYER M3  ;
    ANTENNAPARTIALMETALSIDEAREA 0.0056 LAYER M3  ;
    PORT
      LAYER M2 ;
        RECT 50.300000 0.000000 50.500000 0.600000 ;
    END
  END pk_out_PE_state__2_
  PIN pk_out_PE_state__1_
    DIRECTION OUTPUT ;
    USE SIGNAL ;
    ANTENNAPARTIALMETALAREA 5.74 LAYER M2  ;
    ANTENNAPARTIALMETALSIDEAREA 0.0574 LAYER M2  ;
    ANTENNAPARTIALCUTAREA 0.08 LAYER V2  ;
    ANTENNADIFFAREA 2.014 LAYER M3  ;
    ANTENNAPARTIALMETALAREA 0.76 LAYER M3  ;
    ANTENNAPARTIALMETALSIDEAREA 0.008 LAYER M3  ;
    PORT
      LAYER M2 ;
        RECT 66.300000 0.000000 66.500000 0.600000 ;
    END
  END pk_out_PE_state__1_
  PIN pk_out_PE_state__0_
    DIRECTION OUTPUT ;
    USE SIGNAL ;
    ANTENNADIFFAREA 2.014 LAYER M2  ;
    ANTENNAPARTIALMETALAREA 5.66 LAYER M2  ;
    ANTENNAPARTIALMETALSIDEAREA 0.0566 LAYER M2  ;
    PORT
      LAYER M2 ;
        RECT 82.300000 0.000000 82.500000 0.600000 ;
    END
  END pk_out_PE_state__0_
  PIN pk_out_data__7_
    DIRECTION OUTPUT ;
    USE SIGNAL ;
    PORT
      LAYER M2 ;
        RECT 98.300000 0.000000 98.500000 0.600000 ;
    END
  END pk_out_data__7_
  PIN pk_out_data__6_
    DIRECTION OUTPUT ;
    USE SIGNAL ;
    ANTENNAPARTIALMETALAREA 2.86 LAYER M2  ;
    ANTENNAPARTIALMETALSIDEAREA 0.0286 LAYER M2  ;
    ANTENNAPARTIALCUTAREA 0.08 LAYER V2  ;
    ANTENNADIFFAREA 1.76 LAYER M3  ;
    ANTENNAPARTIALMETALAREA 0.44 LAYER M3  ;
    ANTENNAPARTIALMETALSIDEAREA 0.0048 LAYER M3  ;
    PORT
      LAYER M2 ;
        RECT 114.300000 0.000000 114.500000 0.600000 ;
    END
  END pk_out_data__6_
  PIN pk_out_data__5_
    DIRECTION OUTPUT ;
    USE SIGNAL ;
    ANTENNAPARTIALMETALAREA 2.38 LAYER M2  ;
    ANTENNAPARTIALMETALSIDEAREA 0.0238 LAYER M2  ;
    ANTENNAPARTIALCUTAREA 0.08 LAYER V2  ;
    ANTENNADIFFAREA 1.76 LAYER M3  ;
    ANTENNAPARTIALMETALAREA 1.48 LAYER M3  ;
    ANTENNAPARTIALMETALSIDEAREA 0.0152 LAYER M3  ;
    PORT
      LAYER M2 ;
        RECT 130.300000 0.000000 130.500000 0.600000 ;
    END
  END pk_out_data__5_
  PIN pk_out_data__4_
    DIRECTION OUTPUT ;
    USE SIGNAL ;
    ANTENNAPARTIALMETALAREA 1.5 LAYER M2  ;
    ANTENNAPARTIALMETALSIDEAREA 0.015 LAYER M2  ;
    ANTENNAPARTIALCUTAREA 0.08 LAYER V2  ;
    ANTENNADIFFAREA 1.76 LAYER M3  ;
    ANTENNAPARTIALMETALAREA 3.88 LAYER M3  ;
    ANTENNAPARTIALMETALSIDEAREA 0.0392 LAYER M3  ;
    PORT
      LAYER M2 ;
        RECT 146.300000 0.000000 146.500000 0.600000 ;
    END
  END pk_out_data__4_
  PIN pk_out_data__3_
    DIRECTION OUTPUT ;
    USE SIGNAL ;
    ANTENNAPARTIALMETALAREA 2.78 LAYER M2  ;
    ANTENNAPARTIALMETALSIDEAREA 0.0278 LAYER M2  ;
    ANTENNAPARTIALCUTAREA 0.08 LAYER V2  ;
    ANTENNADIFFAREA 1.76 LAYER M3  ;
    ANTENNAPARTIALMETALAREA 2.04 LAYER M3  ;
    ANTENNAPARTIALMETALSIDEAREA 0.0208 LAYER M3  ;
    PORT
      LAYER M2 ;
        RECT 162.300000 0.000000 162.500000 0.600000 ;
    END
  END pk_out_data__3_
  PIN pk_out_data__2_
    DIRECTION OUTPUT ;
    USE SIGNAL ;
    ANTENNAPARTIALMETALAREA 2.46 LAYER M2  ;
    ANTENNAPARTIALMETALSIDEAREA 0.0246 LAYER M2  ;
    ANTENNAPARTIALCUTAREA 0.08 LAYER V2  ;
    ANTENNADIFFAREA 1.76 LAYER M3  ;
    ANTENNAPARTIALMETALAREA 5.88 LAYER M3  ;
    ANTENNAPARTIALMETALSIDEAREA 0.0592 LAYER M3  ;
    PORT
      LAYER M2 ;
        RECT 178.300000 0.000000 178.500000 0.600000 ;
    END
  END pk_out_data__2_
  PIN pk_out_data__1_
    DIRECTION OUTPUT ;
    USE SIGNAL ;
    ANTENNAPARTIALMETALAREA 0.16 LAYER M2  ;
    ANTENNAPARTIALMETALSIDEAREA 0.0016 LAYER M2  ;
    ANTENNAPARTIALCUTAREA 0.08 LAYER V2  ;
    ANTENNADIFFAREA 1.76 LAYER M3  ;
    ANTENNAPARTIALMETALAREA 9.84 LAYER M3  ;
    ANTENNAPARTIALMETALSIDEAREA 0.0992 LAYER M3  ;
    PORT
      LAYER M2 ;
        RECT 194.300000 0.000000 194.500000 0.600000 ;
    END
  END pk_out_data__1_
  PIN pk_out_data__0_
    DIRECTION OUTPUT ;
    USE SIGNAL ;
    ANTENNAPARTIALMETALAREA 3.82 LAYER M2  ;
    ANTENNAPARTIALMETALSIDEAREA 0.0382 LAYER M2  ;
    ANTENNAPARTIALCUTAREA 0.08 LAYER V2  ;
    ANTENNADIFFAREA 1.76 LAYER M3  ;
    ANTENNAPARTIALMETALAREA 13 LAYER M3  ;
    ANTENNAPARTIALMETALSIDEAREA 0.1304 LAYER M3  ;
    PORT
      LAYER M2 ;
        RECT 210.300000 0.000000 210.500000 0.600000 ;
    END
  END pk_out_data__0_
  PIN VSS
    DIRECTION INOUT ;
    USE GROUND ;

# P/G power stripe data as pin
    PORT
      LAYER M4 ;
        RECT 1.000000 1.000000 3.000000 298.200000 ;
        RECT 26.000000 1.000000 28.000000 298.200000 ;
        RECT 56.000000 1.000000 58.000000 298.200000 ;
        RECT 86.000000 1.000000 88.000000 298.200000 ;
        RECT 116.000000 1.000000 118.000000 298.200000 ;
        RECT 176.000000 1.000000 178.000000 298.200000 ;
        RECT 146.000000 1.000000 148.000000 298.200000 ;
        RECT 206.000000 1.000000 208.000000 298.200000 ;
        RECT 236.000000 1.000000 238.000000 298.200000 ;
        RECT 257.000000 1.000000 259.000000 298.200000 ;
    END
# end of P/G power stripe data as pin

  END VSS
  PIN VDD
    DIRECTION INOUT ;
    USE POWER ;

# P/G power stripe data as pin
    PORT
      LAYER M4 ;
        RECT 4.000000 4.000000 6.000000 295.200000 ;
        RECT 22.000000 4.000000 24.000000 295.200000 ;
        RECT 52.000000 4.000000 54.000000 295.200000 ;
        RECT 82.000000 4.000000 84.000000 295.200000 ;
        RECT 112.000000 4.000000 114.000000 295.200000 ;
        RECT 202.000000 4.000000 204.000000 295.200000 ;
        RECT 172.000000 4.000000 174.000000 295.200000 ;
        RECT 142.000000 4.000000 144.000000 295.200000 ;
        RECT 232.000000 4.000000 234.000000 295.200000 ;
        RECT 254.000000 4.000000 256.000000 295.200000 ;
    END
# end of P/G power stripe data as pin

  END VDD
  OBS
    LAYER M1 ;
      RECT 0.000000 0.000000 260.000000 300.000000 ;
    LAYER M2 ;
      RECT 219.620000 297.480000 260.000000 300.000000 ;
      RECT 211.620000 297.480000 215.580000 300.000000 ;
      RECT 203.620000 297.480000 207.580000 300.000000 ;
      RECT 195.620000 297.480000 199.580000 300.000000 ;
      RECT 187.620000 297.480000 191.580000 300.000000 ;
      RECT 179.620000 297.480000 183.580000 300.000000 ;
      RECT 171.620000 297.480000 175.580000 300.000000 ;
      RECT 163.620000 297.480000 167.580000 300.000000 ;
      RECT 155.620000 297.480000 159.580000 300.000000 ;
      RECT 147.620000 297.480000 151.580000 300.000000 ;
      RECT 139.620000 297.480000 143.580000 300.000000 ;
      RECT 131.620000 297.480000 135.580000 300.000000 ;
      RECT 123.620000 297.480000 127.580000 300.000000 ;
      RECT 115.620000 297.480000 119.580000 300.000000 ;
      RECT 107.620000 297.480000 111.580000 300.000000 ;
      RECT 99.620000 297.480000 103.580000 300.000000 ;
      RECT 91.620000 297.480000 95.580000 300.000000 ;
      RECT 83.620000 297.480000 87.580000 300.000000 ;
      RECT 75.620000 297.480000 79.580000 300.000000 ;
      RECT 67.620000 297.480000 71.580000 300.000000 ;
      RECT 59.620000 297.480000 63.580000 300.000000 ;
      RECT 51.620000 297.480000 55.580000 300.000000 ;
      RECT 43.620000 297.480000 47.580000 300.000000 ;
      RECT 0.000000 297.480000 39.580000 300.000000 ;
      RECT 0.000000 2.520000 260.000000 297.480000 ;
      RECT 212.420000 0.000000 260.000000 2.520000 ;
      RECT 196.420000 0.000000 208.380000 2.520000 ;
      RECT 180.420000 0.000000 192.380000 2.520000 ;
      RECT 164.420000 0.000000 176.380000 2.520000 ;
      RECT 148.420000 0.000000 160.380000 2.520000 ;
      RECT 132.420000 0.000000 144.380000 2.520000 ;
      RECT 116.420000 0.000000 128.380000 2.520000 ;
      RECT 100.420000 0.000000 112.380000 2.520000 ;
      RECT 84.420000 0.000000 96.380000 2.520000 ;
      RECT 68.420000 0.000000 80.380000 2.520000 ;
      RECT 52.420000 0.000000 64.380000 2.520000 ;
      RECT 0.000000 0.000000 48.380000 2.520000 ;
    LAYER M3 ;
      RECT 0.000000 275.620000 260.000000 300.000000 ;
      RECT 2.520000 271.580000 260.000000 275.620000 ;
      RECT 0.000000 267.620000 260.000000 271.580000 ;
      RECT 2.520000 263.580000 260.000000 267.620000 ;
      RECT 0.000000 259.620000 260.000000 263.580000 ;
      RECT 2.520000 255.580000 260.000000 259.620000 ;
      RECT 0.000000 251.620000 260.000000 255.580000 ;
      RECT 2.520000 247.580000 260.000000 251.620000 ;
      RECT 0.000000 243.620000 260.000000 247.580000 ;
      RECT 2.520000 239.580000 260.000000 243.620000 ;
      RECT 0.000000 235.620000 260.000000 239.580000 ;
      RECT 2.520000 231.580000 260.000000 235.620000 ;
      RECT 0.000000 227.620000 260.000000 231.580000 ;
      RECT 2.520000 223.580000 260.000000 227.620000 ;
      RECT 0.000000 219.620000 260.000000 223.580000 ;
      RECT 2.520000 215.580000 260.000000 219.620000 ;
      RECT 0.000000 211.620000 260.000000 215.580000 ;
      RECT 2.520000 207.580000 260.000000 211.620000 ;
      RECT 0.000000 203.620000 260.000000 207.580000 ;
      RECT 2.520000 199.580000 260.000000 203.620000 ;
      RECT 0.000000 195.620000 260.000000 199.580000 ;
      RECT 2.520000 191.580000 260.000000 195.620000 ;
      RECT 0.000000 187.620000 260.000000 191.580000 ;
      RECT 2.520000 183.580000 260.000000 187.620000 ;
      RECT 0.000000 179.620000 260.000000 183.580000 ;
      RECT 2.520000 175.580000 260.000000 179.620000 ;
      RECT 0.000000 171.620000 260.000000 175.580000 ;
      RECT 2.520000 167.580000 260.000000 171.620000 ;
      RECT 0.000000 163.620000 260.000000 167.580000 ;
      RECT 2.520000 159.580000 260.000000 163.620000 ;
      RECT 0.000000 155.620000 260.000000 159.580000 ;
      RECT 2.520000 151.580000 260.000000 155.620000 ;
      RECT 0.000000 147.620000 260.000000 151.580000 ;
      RECT 2.520000 143.580000 260.000000 147.620000 ;
      RECT 0.000000 139.620000 260.000000 143.580000 ;
      RECT 2.520000 135.580000 260.000000 139.620000 ;
      RECT 0.000000 131.620000 260.000000 135.580000 ;
      RECT 2.520000 127.580000 260.000000 131.620000 ;
      RECT 0.000000 123.620000 260.000000 127.580000 ;
      RECT 2.520000 119.580000 260.000000 123.620000 ;
      RECT 0.000000 115.620000 260.000000 119.580000 ;
      RECT 2.520000 111.580000 260.000000 115.620000 ;
      RECT 0.000000 107.620000 260.000000 111.580000 ;
      RECT 2.520000 103.580000 260.000000 107.620000 ;
      RECT 0.000000 99.620000 260.000000 103.580000 ;
      RECT 2.520000 95.580000 260.000000 99.620000 ;
      RECT 0.000000 91.620000 260.000000 95.580000 ;
      RECT 2.520000 87.580000 260.000000 91.620000 ;
      RECT 0.000000 83.620000 260.000000 87.580000 ;
      RECT 2.520000 79.580000 260.000000 83.620000 ;
      RECT 0.000000 75.620000 260.000000 79.580000 ;
      RECT 2.520000 71.580000 260.000000 75.620000 ;
      RECT 0.000000 67.620000 260.000000 71.580000 ;
      RECT 2.520000 63.580000 260.000000 67.620000 ;
      RECT 0.000000 59.620000 260.000000 63.580000 ;
      RECT 2.520000 55.580000 260.000000 59.620000 ;
      RECT 0.000000 51.620000 260.000000 55.580000 ;
      RECT 2.520000 47.580000 260.000000 51.620000 ;
      RECT 0.000000 43.620000 260.000000 47.580000 ;
      RECT 2.520000 39.580000 260.000000 43.620000 ;
      RECT 0.000000 35.620000 260.000000 39.580000 ;
      RECT 2.520000 31.580000 260.000000 35.620000 ;
      RECT 0.000000 27.620000 260.000000 31.580000 ;
      RECT 2.520000 23.580000 260.000000 27.620000 ;
      RECT 0.000000 18.020000 260.000000 23.580000 ;
      RECT 2.520000 13.980000 260.000000 18.020000 ;
      RECT 0.000000 11.220000 260.000000 13.980000 ;
      RECT 2.520000 7.180000 260.000000 11.220000 ;
      RECT 0.000000 0.000000 260.000000 7.180000 ;
    LAYER M4 ;
      RECT 239.920000 297.120000 255.080000 300.000000 ;
      RECT 209.920000 297.120000 234.080000 300.000000 ;
      RECT 179.920000 297.120000 204.080000 300.000000 ;
      RECT 149.920000 297.120000 174.080000 300.000000 ;
      RECT 119.920000 297.120000 144.080000 300.000000 ;
      RECT 89.920000 297.120000 114.080000 300.000000 ;
      RECT 59.920000 297.120000 84.080000 300.000000 ;
      RECT 29.920000 297.120000 54.080000 300.000000 ;
      RECT 4.920000 297.120000 24.080000 300.000000 ;
      RECT 239.920000 2.080000 252.080000 297.120000 ;
      RECT 209.920000 2.080000 230.080000 297.120000 ;
      RECT 179.920000 2.080000 200.080000 297.120000 ;
      RECT 149.920000 2.080000 170.080000 297.120000 ;
      RECT 119.920000 2.080000 140.080000 297.120000 ;
      RECT 89.920000 2.080000 110.080000 297.120000 ;
      RECT 59.920000 2.080000 80.080000 297.120000 ;
      RECT 29.920000 2.080000 50.080000 297.120000 ;
      RECT 7.920000 2.080000 20.080000 297.120000 ;
      RECT 239.920000 0.000000 255.080000 2.080000 ;
      RECT 209.920000 0.000000 234.080000 2.080000 ;
      RECT 179.920000 0.000000 204.080000 2.080000 ;
      RECT 149.920000 0.000000 174.080000 2.080000 ;
      RECT 119.920000 0.000000 144.080000 2.080000 ;
      RECT 89.920000 0.000000 114.080000 2.080000 ;
      RECT 59.920000 0.000000 84.080000 2.080000 ;
      RECT 29.920000 0.000000 54.080000 2.080000 ;
      RECT 4.920000 0.000000 24.080000 2.080000 ;
  END
END PE_POOL

END LIBRARY
